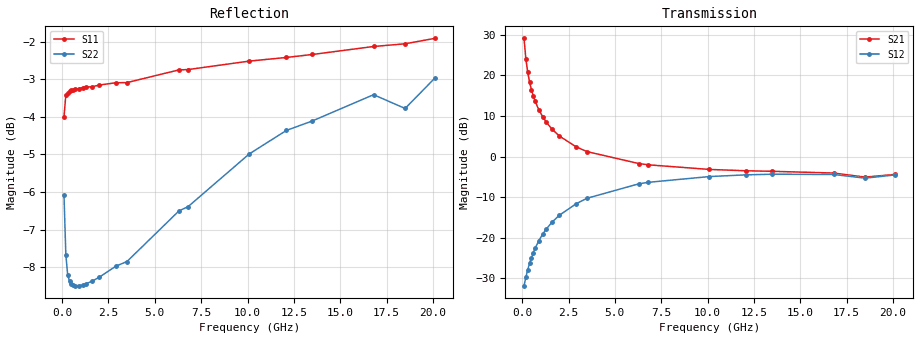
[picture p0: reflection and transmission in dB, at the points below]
!  Infineon Technologies AG
! BFR380L3 , PF131585-7, No.6, Th 09.10.01, soldered on pcb-board, measured with PP GSG850
!  Vce=0.5 V,  Ic=40.0 mA
! Common Emitter S-Parameters:  15. November 2001
#  GHz  S  MA  R  50
! f  S11  S21  S12  S22
! GHz  Mag  Ang  Mag  Ang  Mag  Ang  Mag  Ang
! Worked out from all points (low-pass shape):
!   201 points, 100 MHz to 20.1 GHz, reference 50 ohm
!   highest |S21| = 29.12 dB at 100 MHz (marker M1); lowest = -5.1 dB at 18.5 GHz (marker M2)
!   |S21| within 3 dB of the highest: start of sweep to 159.3 MHz
!   lowest |S11| = -4.0 dB at 100 MHz (marker M3), VSWR 4.41, Z = 13.2 - j19.5 ohm
!   |S11| at or under -10 dB: nowhere
!   |S22| runs from -8.5 to -3.0 dB; largest |S21 - S12| = 29
!   S11 on the Smith chart (normalised r, x): 100 MHz: 0.26, -0.39; 600 MHz: 0.19, +0.00; 2.9 GHz: 0.20, +0.35; 6.3 GHz: 0.26, +0.79; 12.1 GHz: 0.47, +1.50; 20.1 GHz: 0.96, +2.63
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0.1  0.6306 -134.9  28.58 117.3  0.02574 46.6  0.4971 -101.8
0.2  0.6747 -157.8  15.96 102.1  0.03275 49.5  0.4136 -134.9
0.3  0.6779 -167.1  10.92 95.8  0.04053 54.7  0.3889 -149.8
0.4  0.6838 -173.1  8.287 91.6  0.0486 58.4  0.3812 -158.2
0.5  0.6841 -177.1  6.666 88.3  0.05706 61.1  0.3783 -163.7
0.6  0.6848 179.6  5.581 85.7  0.06576 63.0  0.3766 -167.7
0.7  0.687 176.8  4.808 83.3  0.07439 64.1  0.3763 -170.8
0.9  0.6873 172.3  3.766 79.0  0.09248 65.4  0.3764 -175.6
1.1  0.6901 168.3  3.116 75.2  0.1104 65.4  0.3769 -179.1
1.3  0.6911 164.7  2.656 71.7  0.1281 65.1  0.3786 177.8
1.6  0.6915 159.6  2.193 66.6  0.1548 63.8  0.3814 173.9
2  0.6953 153.1  1.798 60.3  0.1891 61.3  0.3861 169.4
2.9  0.7002 140.0  1.323 47.6  0.2617 54.5  0.3995 160.2
3.5  0.7006 131.9  1.152 40.2  0.307 49.5  0.4052 155.0
6.3  0.7283 101.2  0.821 14.2  0.4629 27.6  0.473 131.2
6.8  0.7291 96.5  0.7925 10.6  0.4823 23.8  0.4794 126.8
10.1  0.7482 73.6  0.6953 -7.6  0.568 3.0  0.5633 104.6
12.1  0.7566 63.9  0.6689 -16.5  0.5966 -8.0  0.6052 91.9
13.5  0.7635 57.8  0.6593 -22.8  0.6071 -15.5  0.623 84.0
16.8  0.7824 46.4  0.6277 -34.0  0.6024 -29.3  0.6751 67.7
18.5  0.7889 44.4  0.5588 -41.2  0.5428 -37.1  0.6472 63.9
20.1  0.8021 37.6  0.6038 -44.4  0.5945 -41.5  0.71 54.5
